VERSION 5.7 ;
BUSBITCHARS "[]" ;
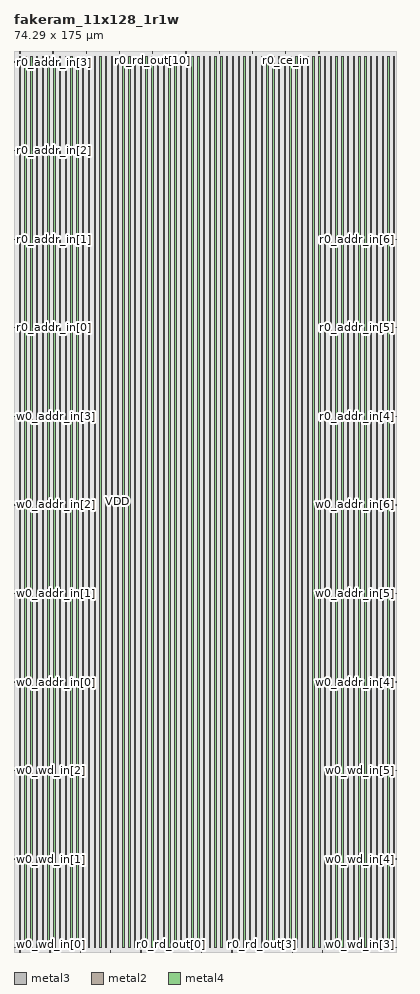
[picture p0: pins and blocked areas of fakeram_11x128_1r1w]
MACRO fakeram_11x128_1r1w
  FOREIGN fakeram_11x128_1r1w 0 0 ;
  SYMMETRY X Y R90 ;
  SIZE 74.290 BY 175.000 ;
  CLASS BLOCK ;
  PIN w0_wd_in[0]
    DIRECTION INPUT ;
    USE SIGNAL ;
    SHAPE ABUTMENT ;
    PORT
      LAYER metal3 ;
      RECT 0.000 0.805 0.210 0.875 ;
    END
  END w0_wd_in[0]
  PIN w0_wd_in[1]
    DIRECTION INPUT ;
    USE SIGNAL ;
    SHAPE ABUTMENT ;
    PORT
      LAYER metal3 ;
      RECT 0.000 18.025 0.210 18.095 ;
    END
  END w0_wd_in[1]
  PIN w0_wd_in[2]
    DIRECTION INPUT ;
    USE SIGNAL ;
    SHAPE ABUTMENT ;
    PORT
      LAYER metal3 ;
      RECT 0.000 35.245 0.210 35.315 ;
    END
  END w0_wd_in[2]
  PIN w0_wd_in[3]
    DIRECTION INPUT ;
    USE SIGNAL ;
    SHAPE ABUTMENT ;
    PORT
      LAYER metal3 ;
      RECT 74.080 0.805 74.290 0.875 ;
    END
  END w0_wd_in[3]
  PIN w0_wd_in[4]
    DIRECTION INPUT ;
    USE SIGNAL ;
    SHAPE ABUTMENT ;
    PORT
      LAYER metal3 ;
      RECT 74.080 18.025 74.290 18.095 ;
    END
  END w0_wd_in[4]
  PIN w0_wd_in[5]
    DIRECTION INPUT ;
    USE SIGNAL ;
    SHAPE ABUTMENT ;
    PORT
      LAYER metal3 ;
      RECT 74.080 35.245 74.290 35.315 ;
    END
  END w0_wd_in[5]
  PIN w0_wd_in[6]
    DIRECTION INPUT ;
    USE SIGNAL ;
    SHAPE ABUTMENT ;
    PORT
      LAYER metal2 ;
      RECT 1.105 0.000 1.175 0.210 ;
    END
  END w0_wd_in[6]
  PIN w0_wd_in[7]
    DIRECTION INPUT ;
    USE SIGNAL ;
    SHAPE ABUTMENT ;
    PORT
      LAYER metal2 ;
      RECT 6.995 0.000 7.065 0.210 ;
    END
  END w0_wd_in[7]
  PIN w0_wd_in[8]
    DIRECTION INPUT ;
    USE SIGNAL ;
    SHAPE ABUTMENT ;
    PORT
      LAYER metal2 ;
      RECT 12.885 0.000 12.955 0.210 ;
    END
  END w0_wd_in[8]
  PIN w0_wd_in[9]
    DIRECTION INPUT ;
    USE SIGNAL ;
    SHAPE ABUTMENT ;
    PORT
      LAYER metal2 ;
      RECT 18.775 0.000 18.845 0.210 ;
    END
  END w0_wd_in[9]
  PIN w0_wd_in[10]
    DIRECTION INPUT ;
    USE SIGNAL ;
    SHAPE ABUTMENT ;
    PORT
      LAYER metal2 ;
      RECT 24.665 0.000 24.735 0.210 ;
    END
  END w0_wd_in[10]
  PIN r0_rd_out[0]
    DIRECTION OUTPUT ;
    USE SIGNAL ;
    SHAPE ABUTMENT ;
    PORT
      LAYER metal2 ;
      RECT 30.555 0.000 30.625 0.210 ;
    END
  END r0_rd_out[0]
  PIN r0_rd_out[1]
    DIRECTION OUTPUT ;
    USE SIGNAL ;
    SHAPE ABUTMENT ;
    PORT
      LAYER metal2 ;
      RECT 36.445 0.000 36.515 0.210 ;
    END
  END r0_rd_out[1]
  PIN r0_rd_out[2]
    DIRECTION OUTPUT ;
    USE SIGNAL ;
    SHAPE ABUTMENT ;
    PORT
      LAYER metal2 ;
      RECT 42.335 0.000 42.405 0.210 ;
    END
  END r0_rd_out[2]
  PIN r0_rd_out[3]
    DIRECTION OUTPUT ;
    USE SIGNAL ;
    SHAPE ABUTMENT ;
    PORT
      LAYER metal2 ;
      RECT 48.225 0.000 48.295 0.210 ;
    END
  END r0_rd_out[3]
  PIN r0_rd_out[4]
    DIRECTION OUTPUT ;
    USE SIGNAL ;
    SHAPE ABUTMENT ;
    PORT
      LAYER metal2 ;
      RECT 54.115 0.000 54.185 0.210 ;
    END
  END r0_rd_out[4]
  PIN r0_rd_out[5]
    DIRECTION OUTPUT ;
    USE SIGNAL ;
    SHAPE ABUTMENT ;
    PORT
      LAYER metal2 ;
      RECT 60.005 0.000 60.075 0.210 ;
    END
  END r0_rd_out[5]
  PIN r0_rd_out[6]
    DIRECTION OUTPUT ;
    USE SIGNAL ;
    SHAPE ABUTMENT ;
    PORT
      LAYER metal2 ;
      RECT 1.105 174.790 1.175 175.000 ;
    END
  END r0_rd_out[6]
  PIN r0_rd_out[7]
    DIRECTION OUTPUT ;
    USE SIGNAL ;
    SHAPE ABUTMENT ;
    PORT
      LAYER metal2 ;
      RECT 7.565 174.790 7.635 175.000 ;
    END
  END r0_rd_out[7]
  PIN r0_rd_out[8]
    DIRECTION OUTPUT ;
    USE SIGNAL ;
    SHAPE ABUTMENT ;
    PORT
      LAYER metal2 ;
      RECT 14.025 174.790 14.095 175.000 ;
    END
  END r0_rd_out[8]
  PIN r0_rd_out[9]
    DIRECTION OUTPUT ;
    USE SIGNAL ;
    SHAPE ABUTMENT ;
    PORT
      LAYER metal2 ;
      RECT 20.485 174.790 20.555 175.000 ;
    END
  END r0_rd_out[9]
  PIN r0_rd_out[10]
    DIRECTION OUTPUT ;
    USE SIGNAL ;
    SHAPE ABUTMENT ;
    PORT
      LAYER metal2 ;
      RECT 26.945 174.790 27.015 175.000 ;
    END
  END r0_rd_out[10]
  PIN w0_addr_in[0]
    DIRECTION INPUT ;
    USE SIGNAL ;
    SHAPE ABUTMENT ;
    PORT
      LAYER metal3 ;
      RECT 0.000 52.465 0.210 52.535 ;
    END
  END w0_addr_in[0]
  PIN w0_addr_in[1]
    DIRECTION INPUT ;
    USE SIGNAL ;
    SHAPE ABUTMENT ;
    PORT
      LAYER metal3 ;
      RECT 0.000 69.685 0.210 69.755 ;
    END
  END w0_addr_in[1]
  PIN w0_addr_in[2]
    DIRECTION INPUT ;
    USE SIGNAL ;
    SHAPE ABUTMENT ;
    PORT
      LAYER metal3 ;
      RECT 0.000 86.905 0.210 86.975 ;
    END
  END w0_addr_in[2]
  PIN w0_addr_in[3]
    DIRECTION INPUT ;
    USE SIGNAL ;
    SHAPE ABUTMENT ;
    PORT
      LAYER metal3 ;
      RECT 0.000 104.125 0.210 104.195 ;
    END
  END w0_addr_in[3]
  PIN w0_addr_in[4]
    DIRECTION INPUT ;
    USE SIGNAL ;
    SHAPE ABUTMENT ;
    PORT
      LAYER metal3 ;
      RECT 74.080 52.465 74.290 52.535 ;
    END
  END w0_addr_in[4]
  PIN w0_addr_in[5]
    DIRECTION INPUT ;
    USE SIGNAL ;
    SHAPE ABUTMENT ;
    PORT
      LAYER metal3 ;
      RECT 74.080 69.685 74.290 69.755 ;
    END
  END w0_addr_in[5]
  PIN w0_addr_in[6]
    DIRECTION INPUT ;
    USE SIGNAL ;
    SHAPE ABUTMENT ;
    PORT
      LAYER metal3 ;
      RECT 74.080 86.905 74.290 86.975 ;
    END
  END w0_addr_in[6]
  PIN r0_addr_in[0]
    DIRECTION INPUT ;
    USE SIGNAL ;
    SHAPE ABUTMENT ;
    PORT
      LAYER metal3 ;
      RECT 0.000 121.345 0.210 121.415 ;
    END
  END r0_addr_in[0]
  PIN r0_addr_in[1]
    DIRECTION INPUT ;
    USE SIGNAL ;
    SHAPE ABUTMENT ;
    PORT
      LAYER metal3 ;
      RECT 0.000 138.565 0.210 138.635 ;
    END
  END r0_addr_in[1]
  PIN r0_addr_in[2]
    DIRECTION INPUT ;
    USE SIGNAL ;
    SHAPE ABUTMENT ;
    PORT
      LAYER metal3 ;
      RECT 0.000 155.785 0.210 155.855 ;
    END
  END r0_addr_in[2]
  PIN r0_addr_in[3]
    DIRECTION INPUT ;
    USE SIGNAL ;
    SHAPE ABUTMENT ;
    PORT
      LAYER metal3 ;
      RECT 0.000 173.005 0.210 173.075 ;
    END
  END r0_addr_in[3]
  PIN r0_addr_in[4]
    DIRECTION INPUT ;
    USE SIGNAL ;
    SHAPE ABUTMENT ;
    PORT
      LAYER metal3 ;
      RECT 74.080 104.125 74.290 104.195 ;
    END
  END r0_addr_in[4]
  PIN r0_addr_in[5]
    DIRECTION INPUT ;
    USE SIGNAL ;
    SHAPE ABUTMENT ;
    PORT
      LAYER metal3 ;
      RECT 74.080 121.345 74.290 121.415 ;
    END
  END r0_addr_in[5]
  PIN r0_addr_in[6]
    DIRECTION INPUT ;
    USE SIGNAL ;
    SHAPE ABUTMENT ;
    PORT
      LAYER metal3 ;
      RECT 74.080 138.565 74.290 138.635 ;
    END
  END r0_addr_in[6]
  PIN w0_we_in
    DIRECTION INPUT ;
    USE SIGNAL ;
    SHAPE ABUTMENT ;
    PORT
      LAYER metal2 ;
      RECT 33.405 174.790 33.475 175.000 ;
    END
  END w0_we_in
  PIN w0_ce_in
    DIRECTION INPUT ;
    USE SIGNAL ;
    SHAPE ABUTMENT ;
    PORT
      LAYER metal2 ;
      RECT 39.865 174.790 39.935 175.000 ;
    END
  END w0_ce_in
  PIN w0_clk
    DIRECTION INPUT ;
    USE SIGNAL ;
    SHAPE ABUTMENT ;
    PORT
      LAYER metal2 ;
      RECT 46.325 174.790 46.395 175.000 ;
    END
  END w0_clk
  PIN r0_ce_in
    DIRECTION INPUT ;
    USE SIGNAL ;
    SHAPE ABUTMENT ;
    PORT
      LAYER metal2 ;
      RECT 52.785 174.790 52.855 175.000 ;
    END
  END r0_ce_in
  PIN r0_clk
    DIRECTION INPUT ;
    USE SIGNAL ;
    SHAPE ABUTMENT ;
    PORT
      LAYER metal2 ;
      RECT 59.245 174.790 59.315 175.000 ;
    END
  END r0_clk
  PIN VSS
    DIRECTION INOUT ;
    USE GROUND ;
    PORT
      LAYER metal4 ;
      RECT 1.000 0.840 1.280 174.160 ;
      RECT 3.240 0.840 3.520 174.160 ;
      RECT 5.480 0.840 5.760 174.160 ;
      RECT 7.720 0.840 8.000 174.160 ;
      RECT 9.960 0.840 10.240 174.160 ;
      RECT 12.200 0.840 12.480 174.160 ;
      RECT 14.440 0.840 14.720 174.160 ;
      RECT 16.680 0.840 16.960 174.160 ;
      RECT 18.920 0.840 19.200 174.160 ;
      RECT 21.160 0.840 21.440 174.160 ;
      RECT 23.400 0.840 23.680 174.160 ;
      RECT 25.640 0.840 25.920 174.160 ;
      RECT 27.880 0.840 28.160 174.160 ;
      RECT 30.120 0.840 30.400 174.160 ;
      RECT 32.360 0.840 32.640 174.160 ;
      RECT 34.600 0.840 34.880 174.160 ;
      RECT 36.840 0.840 37.120 174.160 ;
      RECT 39.080 0.840 39.360 174.160 ;
      RECT 41.320 0.840 41.600 174.160 ;
      RECT 43.560 0.840 43.840 174.160 ;
      RECT 45.800 0.840 46.080 174.160 ;
      RECT 48.040 0.840 48.320 174.160 ;
      RECT 50.280 0.840 50.560 174.160 ;
      RECT 52.520 0.840 52.800 174.160 ;
      RECT 54.760 0.840 55.040 174.160 ;
      RECT 57.000 0.840 57.280 174.160 ;
      RECT 59.240 0.840 59.520 174.160 ;
      RECT 61.480 0.840 61.760 174.160 ;
      RECT 63.720 0.840 64.000 174.160 ;
      RECT 65.960 0.840 66.240 174.160 ;
      RECT 68.200 0.840 68.480 174.160 ;
      RECT 70.440 0.840 70.720 174.160 ;
      RECT 72.680 0.840 72.960 174.160 ;
    END
  END VSS
  PIN VDD
    DIRECTION INOUT ;
    USE POWER ;
    PORT
      LAYER metal4 ;
      RECT 2.120 0.840 2.400 174.160 ;
      RECT 4.360 0.840 4.640 174.160 ;
      RECT 6.600 0.840 6.880 174.160 ;
      RECT 8.840 0.840 9.120 174.160 ;
      RECT 11.080 0.840 11.360 174.160 ;
      RECT 13.320 0.840 13.600 174.160 ;
      RECT 15.560 0.840 15.840 174.160 ;
      RECT 17.800 0.840 18.080 174.160 ;
      RECT 20.040 0.840 20.320 174.160 ;
      RECT 22.280 0.840 22.560 174.160 ;
      RECT 24.520 0.840 24.800 174.160 ;
      RECT 26.760 0.840 27.040 174.160 ;
      RECT 29.000 0.840 29.280 174.160 ;
      RECT 31.240 0.840 31.520 174.160 ;
      RECT 33.480 0.840 33.760 174.160 ;
      RECT 35.720 0.840 36.000 174.160 ;
      RECT 37.960 0.840 38.240 174.160 ;
      RECT 40.200 0.840 40.480 174.160 ;
      RECT 42.440 0.840 42.720 174.160 ;
      RECT 44.680 0.840 44.960 174.160 ;
      RECT 46.920 0.840 47.200 174.160 ;
      RECT 49.160 0.840 49.440 174.160 ;
      RECT 51.400 0.840 51.680 174.160 ;
      RECT 53.640 0.840 53.920 174.160 ;
      RECT 55.880 0.840 56.160 174.160 ;
      RECT 58.120 0.840 58.400 174.160 ;
      RECT 60.360 0.840 60.640 174.160 ;
      RECT 62.600 0.840 62.880 174.160 ;
      RECT 64.840 0.840 65.120 174.160 ;
      RECT 67.080 0.840 67.360 174.160 ;
      RECT 69.320 0.840 69.600 174.160 ;
      RECT 71.560 0.840 71.840 174.160 ;
      RECT 73.800 0.840 74.080 174.160 ;
    END
  END VDD
  OBS
    LAYER metal1 ;
    RECT 0 0 74.290 175.000 ;
    LAYER metal2 ;
    RECT 0 0 74.290 175.000 ;
    LAYER metal3 ;
    RECT 0 0 74.290 175.000 ;
    LAYER metal4 ;
    RECT 0 0 74.290 175.000 ;
    LAYER OVERLAP ;
    RECT 0 0 74.290 175.000 ;
  END
END fakeram_11x128_1r1w

END LIBRARY
